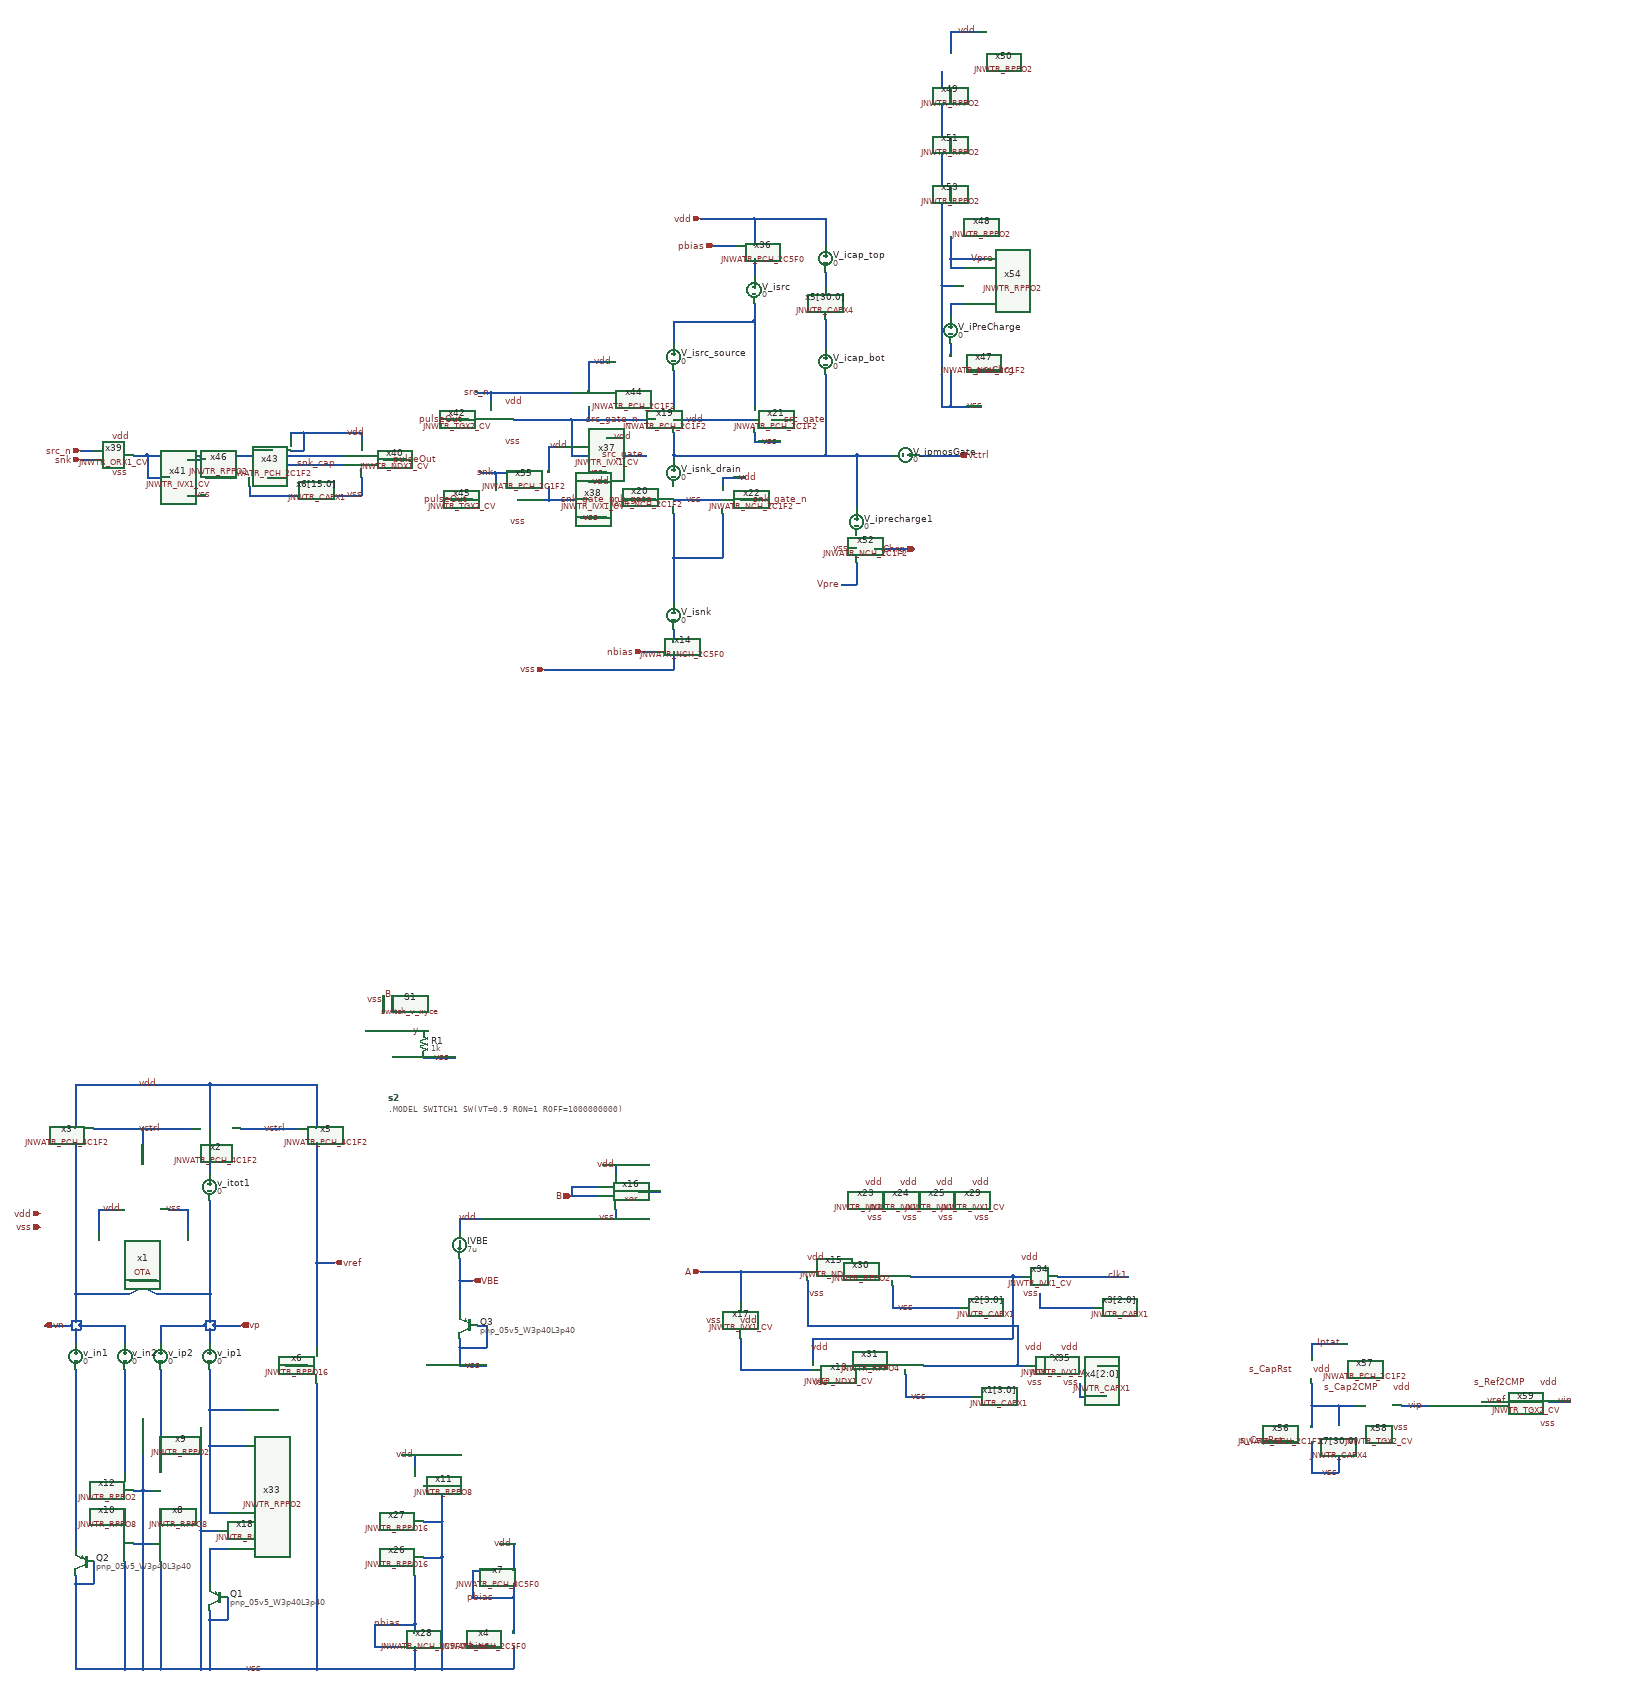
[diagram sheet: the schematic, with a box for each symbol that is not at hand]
v {xschem version=3.4.6 file_version=1.2}
G {}
K {}
V {}
S {}
E {}
N 870 -120 960 -120 {
lab=nbias}
N 960 -120 960 -100 {
lab=nbias}
N 1180 -210 1180 -180 {
lab=pbias}
N 1090 -180 1180 -180 {
lab=pbias}
N 1090 -240 1090 -180 {
lab=pbias}
N 1090 -240 1140 -240 {
lab=pbias}
N 1180 -300 1180 -240 {
lab=vdd}
N 960 -70 960 -20 {
lab=vss}
N 930 -500 960 -500 {
lab=vdd}
N 1020 -270 1020 -20 {
lab=vss}
N 980 -270 1020 -270 {
lab=vss}
N 1020 -350 1020 -270 {
lab=vss}
N 980 -350 1020 -350 {
lab=vss}
N 1020 -430 1020 -350 {
lab=vss}
N 980 -430 1020 -430 {
lab=vss}
N 960 -500 960 -470 {
lab=vdd}
N 1090 -70 1140 -70 {
lab=nbias}
N 1020 -20 1180 -20 {
lab=vss}
N 1150 -300 1180 -300 {
lab=vdd}
N 870 -120 870 -70 {
lab=nbias}
N 870 -70 920 -70 {
lab=nbias}
N 1180 -70 1180 -20 {
lab=vss}
N 1180 -180 1180 -100 {
lab=pbias}
N 960 -230 960 -120 {
lab=nbias}
N 490 -790 490 -780 {
lab=vp}
N 500 -800 510 -800 {
lab=vp}
N 210 -790 210 -780 {
lab=vn}
N 200 -800 210 -800 {
lab=vn}
N 510 -790 510 -780 {
lab=vp}
N 210 -800 210 -790 {
lab=vn}
N 490 -800 490 -790 {
lab=vp}
N 390 -790 490 -790 {
lab=vp}
N 200 -780 210 -780 {
lab=vn}
N 210 -790 310 -790 {
lab=vn}
N 190 -790 190 -780 {
lab=vn}
N 240 -260 240 -210 {
lab=vss}
N 200 -210 240 -210 {
lab=vss}
N 200 -230 200 -210 {
lab=vss}
N 540 -180 540 -130 {
lab=vss}
N 500 -130 540 -130 {
lab=vss}
N 500 -150 500 -130 {
lab=vss}
N 500 -780 510 -780 {
lab=vp}
N 380 -860 500 -860 {
lab=vp}
N 200 -860 200 -800 {
lab=vn}
N 190 -800 200 -800 {
lab=vn}
N 500 -860 500 -800 {
lab=vp}
N 490 -800 500 -800 {
lab=vp}
N 200 -1200 200 -860 {
lab=vn}
N 200 -860 320 -860 {
lab=vn}
N 350 -1230 350 -1150 {
lab=vctrl}
N 350 -1230 460 -1230 {
lab=vctrl}
N 240 -1230 350 -1230 {
lab=vctrl}
N 200 -1330 200 -1230 {
lab=vdd}
N 200 -1330 500 -1330 {
lab=vdd}
N 740 -1330 740 -1230 {
lab=vdd}
N 500 -1330 740 -1330 {
lab=vdd}
N 500 -1330 500 -1230 {
lab=vdd}
N 740 -930 740 -740 {
lab=vref}
N 510 -790 570 -790 {
lab=vp}
N 510 -800 510 -790 {
lab=vp}
N 130 -790 190 -790 {
lab=vn}
N 190 -800 190 -790 {
lab=vn}
N 740 -930 780 -930 {
lab=vref}
N 740 -1200 740 -930 {
lab=vref}
N 570 -1230 700 -1230 {
lab=vctrl}
N 500 -130 500 -20 {
lab=vss}
N 200 -210 200 -20 {
lab=vss}
N 500 -20 740 -20 {
lab=vss}
N 670 -700 720 -700 {
lab=vss}
N 740 -660 740 -20 {
lab=vss}
N 960 -20 1020 -20 {
lab=vss}
N 740 -20 960 -20 {
lab=vss}
N 480 -20 500 -20 {
lab=vss}
N 500 -1200 500 -1130 {
lab=#net1}
N 500 -780 500 -750 {
lab=vp}
N 490 -780 500 -780 {
lab=vp}
N 390 -790 390 -750 {
lab=vp}
N 200 -780 200 -750 {
lab=vn}
N 190 -780 200 -780 {
lab=vn}
N 200 -690 200 -290 {
lab=#net2}
N 310 -790 310 -750 {
lab=vn}
N 1060 -890 1060 -820 {
lab=VBE}
N 1060 -740 1060 -700 {
lab=vss}
N 1060 -700 1120 -700 {
lab=vss}
N 1060 -1030 1060 -1000 {
lab=vdd}
N 1060 -1030 1110 -1030 {
lab=vdd}
N 1060 -890 1090 -890 {
lab=VBE}
N 1060 -940 1060 -890 {
lab=VBE}
N 1100 -790 1120 -790 {
lab=vss}
N 1120 -790 1120 -740 {
lab=vss}
N 1060 -740 1120 -740 {
lab=vss}
N 1060 -760 1060 -740 {
lab=vss}
N 1310 -1100 1370 -1100 {
lab=B}
N 1310 -1080 1370 -1080 {
lab=B}
N 1410 -1150 1410 -1130 {
lab=vdd}
N 1380 -1150 1410 -1150 {
lab=vdd}
N 1410 -1050 1410 -1030 {
lab=vss}
N 1380 -1030 1410 -1030 {
lab=vss}
N 1460 -1090 1510 -1090 {
lab=#net3}
N 500 -520 500 -370 {
lab=#net4}
N 350 -300 370 -300 {
lab=vss}
N 330 -300 350 -300 {
lab=vss}
N 350 -420 370 -420 {
lab=vss}
N 330 -420 350 -420 {
lab=vss}
N 350 -420 350 -300 {
lab=vss}
N 350 -580 350 -420 {
lab=vss}
N 500 -520 580 -520 {
lab=#net4}
N 500 -600 580 -600 {
lab=#net4}
N 310 -690 310 -460 {
lab=#net5}
N 390 -690 390 -460 {
lab=#net6}
N 500 -690 500 -600 {
lab=#net4}
N 500 -290 500 -210 {
lab=#net7}
N 480 -330 480 -20 {
lab=vss}
N 390 -20 480 -20 {
lab=vss}
N 350 -300 350 -20 {
lab=vss}
N 310 -260 310 -20 {
lab=vss}
N 200 -20 310 -20 {
lab=vss}
N 390 -260 390 -20 {
lab=vss}
N 350 -20 390 -20 {
lab=vss}
N 310 -20 350 -20 {
lab=vss}
N 500 -1070 500 -860 {
lab=vp}
N 320 -860 380 -890 {
lab=vn}
N 320 -890 380 -860 {
lab=vp}
N 250 -1050 250 -1000 {
lab=vdd}
N 250 -1050 290 -1050 {
lab=vdd}
N 450 -1050 450 -1000 {
lab=vss}
N 410 -1050 450 -1050 {
lab=vss}
N 940 -1450 980 -1450 {
lab=y}
N 890 -1530 890 -1490 {
lab=vss}
N 910 -1530 910 -1490 {
lab=B}
N 850 -1450 880 -1450 {
lab=#net8}
N 980 -1390 1050 -1390 {
lab=vss}
N 1690 -760 1690 -690 {
lab=#net9}
N 1690 -690 1850 -690 {
lab=#net9}
N 1690 -910 1840 -910 {
lab=A}
N 1690 -910 1690 -840 {
lab=A}
N 1600 -910 1690 -910 {
lab=A}
N 1940 -700 2020 -700 {
lab=#net10}
N 2310 -790 2310 -700 {
lab=#net11}
N 1840 -790 2310 -790 {
lab=#net11}
N 1840 -890 1840 -790 {
lab=#net11}
N 1930 -900 1990 -900 {
lab=#net12}
N 2300 -900 2300 -760 {
lab=#net13}
N 1850 -760 2300 -760 {
lab=#net13}
N 1850 -760 1850 -710 {
lab=#net13}
N 1310 -1100 1310 -1080 {
lab=B}
N 2300 -900 2320 -900 {
lab=#net13}
N 2060 -680 2060 -630 {
lab=vss}
N 2100 -700 2310 -700 {
lab=#net11}
N 2060 -630 2210 -630 {
lab=vss}
N 2030 -880 2030 -830 {
lab=vss}
N 2070 -900 2300 -900 {
lab=#net13}
N 2030 -830 2180 -830 {
lab=vss}
N 2310 -700 2330 -700 {
lab=#net11}
N 2400 -900 2560 -900 {
lab=clk1}
N 2490 -700 2530 -700 {
lab=clk2}
N 2450 -660 2450 -630 {
lab=vss}
N 2450 -630 2510 -630 {
lab=vss}
N 2360 -860 2360 -830 {
lab=vss}
N 2360 -830 2480 -830 {
lab=vss}
N 480 -330 520 -330 {lab=vss}
N 480 -560 480 -330 {
lab=vss}
N 500 -370 540 -370 {lab=#net4}
N 500 -290 540 -290 {lab=#net7}
N 500 -600 500 -520 {lab=#net4}
N 390 -380 390 -340 {lab=#net14}
N 310 -380 310 -340 {lab=#net15}
N 1600 -3270 1720 -3270 {
lab=vdd}
N 1720 -3270 1720 -3210 {
lab=vdd}
N 1540 -2300 1540 -2260 {
lab=vss}
N 1630 -3210 1680 -3210 {
lab=pbias}
N 1470 -2300 1500 -2300 {
lab=nbias}
N 2160 -3180 2240 -3180 {
lab=Vpre}
N 1540 -2790 1540 -2740 {
lab=#net16}
N 1720 -2790 1720 -2770 {
lab=vss}
N 1720 -2770 1780 -2770 {
lab=vss}
N 1760 -2820 1785 -2820 {
lab=src_gate}
N 1650 -2690 1650 -2670 {
lab=vdd}
N 1650 -2690 1700 -2690 {
lab=vdd}
N 1690 -2640 1740 -2640 {
lab=snk_gate_n}
N 1540 -2350 1540 -2320 {
lab=#net17}
N 1720 -3180 1720 -3140 {
lab=#net18}
N 600 -2740 800 -2740 {
lab=#net19}
N 840 -2790 840 -2770 {
lab=vdd}
N 840 -2690 840 -2650 {
lab=vss}
N 360 -2740 360 -2690 {
lab=#net19}
N 650 -2720 650 -2690 {
lab=snk_cap}
N 650 -2720 800 -2720 {
lab=snk_cap}
N 590 -2670 590 -2650 {
lab=vss}
N 630 -2690 650 -2690 {
lab=snk_cap}
N 1350 -2820 1500 -2820 {
lab=src_gate_n}
N 1385 -2700 1390 -2700 {
lab=vss}
N 1390 -2780 1405 -2780 {
lab=vdd}
N 1310 -2820 1310 -2740 {
lab=src_gate_n}
N 1310 -2740 1350 -2740 {
lab=src_gate_n}
N 1430 -2740 1480 -2740 {
lab=src_gate}
N 1430 -2640 1500 -2640 {
lab=snk_gate}
N 1350 -2680 1390 -2680 {
lab=vdd}
N 490 -2690 550 -2690 {
lab=#net20}
N 360 -2690 410 -2690 {
lab=#net19}
N 450 -2650 490 -2650 {
lab=vss}
N 450 -2730 490 -2730 {
lab=vdd}
N 590 -2650 840 -2650 {
lab=vss}
N 1330 -2600 1390 -2600 {
lab=vss}
N 330 -2740 360 -2740 {
lab=#net19}
N 680 -2790 680 -2780 {
lab=vdd}
N 710 -2790 840 -2790 {
lab=vdd}
N 600 -2750 640 -2750 {
lab=#net19}
N 600 -2750 600 -2740 {
lab=#net19}
N 360 -2740 600 -2740 {
lab=#net19}
N 680 -2750 710 -2750 {
lab=vdd}
N 710 -2790 710 -2750 {
lab=vdd}
N 680 -2790 710 -2790 {
lab=vdd}
N 2160 -2930 2160 -2850 {
lab=vss}
N 2200 -2930 2270 -2930 {
lab=preChrg}
N 2160 -2990 2160 -2960 {
lab=#net21}
N 2160 -3080 2160 -3050 {
lab=#net22}
N 2160 -2850 2230 -2850 {
lab=vss}
N 2140 -2850 2160 -2850 {
lab=vss}
N 2160 -3560 2160 -3530 {
lab=#net23}
N 2160 -3690 2160 -3640 {
lab=vdd}
N 2160 -3690 2220 -3690 {
lab=vdd}
N 2160 -3450 2160 -3420 {
lab=#net24}
N 1540 -2740 1540 -2730 {
lab=#net16}
N 1540 -3040 1720 -3040 {
lab=#net25}
N 1720 -3080 1720 -3040 {
lab=#net25}
N 1720 -3270 1880 -3270 {
lab=vdd}
N 1540 -2820 1720 -2820 {
lab=vdd}
N 1540 -2640 1650 -2640 {
lab=vss}
N 1540 -2510 1540 -2410 {
lab=#net26}
N 1650 -2610 1650 -2510 {
lab=#net26}
N 1540 -2510 1650 -2510 {
lab=#net26}
N 1540 -2610 1540 -2510 {
lab=#net26}
N 1720 -3040 1720 -2850 {
lab=#net25}
N 1880 -3045 1880 -2980 {
lab=#net27}
N 1880 -2920 1880 -2740 {
lab=#net16}
N 1540 -2740 1880 -2740 {
lab=#net16}
N 1950 -2740 2030 -2740 {
lab=#net16}
N 2090 -2740 2180 -2740 {
lab=vctrl}
N 1880 -3150 1880 -3115 {
lab=#net28}
N 1880 -3270 1880 -3210 {
lab=vdd}
N 1540 -3040 1540 -2990 {
lab=#net25}
N 1540 -2930 1540 -2850 {
lab=#net29}
N 1990 -2530 2080 -2530 {
lab=preChrg}
N 1935 -2530 1950 -2530 {
lab=vss}
N 1950 -2500 1950 -2450 {
lab=Vpre}
N 1915 -2450 1950 -2450 {
lab=Vpre}
N 1950 -2740 1950 -2620 {
lab=#net16}
N 1880 -2740 1950 -2740 {
lab=#net16}
N 2160 -3180 2160 -3160 {lab=Vpre}
N 2140 -3120 2140 -2850 {
lab=vss}
N 2160 -3160 2190 -3160 {lab=Vpre}
N 2160 -3080 2190 -3080 {lab=#net22}
N 2140 -3120 2170 -3120 {lab=vss}
N 2160 -3230 2160 -3180 {lab=Vpre}
N 2160 -3340 2160 -3310 {lab=#net30}
N 2140 -3600 2140 -3120 {
lab=vss}
N 210 -2730 240 -2730 {lab=snk}
N 210 -2750 240 -2750 {lab=src_n}
N 890 -2730 940 -2730 {lab=pulseOut}
N 1130 -2880 1130 -2860 {lab=src_n}
N 1100 -2880 1130 -2880 {lab=src_n}
N 1180 -2820 1310 -2820 {lab=src_gate_n}
N 1030 -2820 1080 -2820 {lab=pulseOut}
N 1350 -2850 1350 -2820 {lab=src_gate_n}
N 1310 -2820 1350 -2820 {
lab=src_gate_n}
N 1350 -2950 1350 -2880 {lab=vdd}
N 1350 -2950 1390 -2950 {lab=vdd}
N 1130 -2880 1310 -2880 {lab=src_n}
N 1140 -2700 1140 -2680 {lab=snk}
N 1110 -2700 1140 -2700 {lab=snk}
N 1040 -2640 1090 -2640 {lab=pulseOut}
N 1260 -2640 1350 -2640 {lab=snk_gate_n}
N 1250 -2260 1540 -2260 {
lab=vss}
N 1140 -2700 1220 -2700 {lab=snk}
N 1260 -2760 1260 -2700 {lab=vdd}
N 1260 -2760 1280 -2760 {lab=vdd}
N 1260 -2670 1260 -2640 {lab=snk_gate_n}
N 1190 -2640 1260 -2640 {lab=snk_gate_n}
N 2970 -460 3030 -460 {lab=vss}
N 3030 -495 3030 -460 {lab=vss}
N 2970 -530 2970 -460 {lab=vss}
N 2870 -530 2930 -530 {lab=s_CapRst}
N 3030 -610 3030 -565 {lab=#net1}
N 3030 -610 3070 -610 {lab=#net1}
N 2970 -610 2970 -560 {lab=#net1}
N 2970 -610 3030 -610 {lab=#net1}
N 2970 -660 2970 -610 {lab=#net1}
N 2970 -750 2970 -720 {lab=Iptat}
N 2970 -750 3030 -750 {lab=Iptat}
N 3170 -610 3230 -610 {lab=vip}
N 3350 -620 3400 -620 {lab=vref}
N 3500 -620 3550 -620 {lab=vin}
C {devices/ipin.sym} 120 -1010 0 0 {name=p4 lab=vss}
C {devices/ipin.sym} 120 -1040 0 0 {name=p5 lab=vdd}
C {devices/lab_wire.sym} 1140 -180 0 0 {name=p32 sig_type=std_logic lab=pbias}
C {devices/lab_wire.sym} 960 -500 0 0 {name=p34 sig_type=std_logic lab=vdd}
C {JNW_ATR_SKY130A/JNWATR_PCH_8C5F0.sym} 1140 -240 0 0 {name=x7 }
C {JNW_ATR_SKY130A/JNWATR_NCH_2C5F0.sym} 920 -70 0 0 {name=x28 }
C {devices/lab_wire.sym} 930 -120 0 0 {name=p12 sig_type=std_logic lab=nbias}
C {devices/lab_wire.sym} 1180 -300 0 0 {name=p13 sig_type=std_logic lab=vdd}
C {JNW_ATR_SKY130A/JNWATR_NCH_2C5F0.sym} 1140 -70 0 0 {name=x4 }
C {devices/lab_wire.sym} 1130 -70 0 0 {name=p14 sig_type=std_logic lab=nbias}
C {JNW_TR_SKY130A/JNWTR_RPPO16.sym} 960 -230 3 0 {name=x26 }
C {JNW_TR_SKY130A/JNWTR_RPPO16.sym} 960 -310 3 0 {name=x27 }
C {JNW_TR_SKY130A/JNWTR_RPPO8.sym} 960 -390 3 0 {name=x11 }
C {sky130_fd_pr/pnp_05v5.sym} 520 -180 0 1 {name=Q1
model=pnp_05v5_W3p40L3p40
m=8
spiceprefix=X
}
C {sky130_fd_pr/pnp_05v5.sym} 220 -260 0 1 {name=Q2
model=pnp_05v5_W3p40L3p40
m=1
spiceprefix=X
}
C {devices/lab_wire.sym} 340 -1330 0 1 {name=p29 sig_type=std_logic lab=vdd

}
C {devices/opin.sym} 130 -790 2 0 {name=p44 lab=vn}
C {JNW_ATR_SKY130A/JNWATR_PCH_4C1F2.sym} 460 -1230 0 0 {name=x2 }
C {JNW_ATR_SKY130A/JNWATR_PCH_4C1F2.sym} 240 -1230 0 1 {name=x3 }
C {JNW_ATR_SKY130A/JNWATR_PCH_4C1F2.sym} 700 -1230 0 0 {name=x5 }
C {devices/lab_wire.sym} 340 -1230 0 1 {name=p8 sig_type=std_logic lab=vctrl

}
C {devices/lab_wire.sym} 620 -1230 0 1 {name=p9 sig_type=std_logic lab=vctrl

}
C {devices/lab_wire.sym} 620 -20 0 0 {name=p3 sig_type=std_logic lab=vss
}
C {devices/opin.sym} 570 -790 0 0 {name=p7 lab=vp}
C {devices/opin.sym} 780 -930 0 0 {name=p10 lab=vref}
C {devices/lab_wire.sym} 700 -700 0 0 {name=p11 sig_type=std_logic lab=vss
}
C {JNW_TR_SKY130A/JNWTR_RPPO16.sym} 740 -740 1 0 {name=x6 }
C {devices/vsource.sym} 500 -1100 0 0 {name=v_itot1 value=0 savecurrent=true}
C {devices/vsource.sym} 500 -720 0 0 {name=v_ip1 value=0 savecurrent=true}
C {devices/vsource.sym} 390 -720 0 0 {name=v_ip2 value=0 savecurrent=true}
C {devices/vsource.sym} 200 -720 0 0 {name=v_in1 value=0 savecurrent=true}
C {devices/vsource.sym} 310 -720 0 0 {name=v_in2 value=0 savecurrent=true}
C {devices/isource.sym} 1060 -970 0 0 {name=IVBE value=7u}
C {devices/lab_wire.sym} 1100 -1030 0 0 {name=p15 sig_type=std_logic lab=vdd}
C {devices/lab_wire.sym} 1110 -700 0 0 {name=p16 sig_type=std_logic lab=vss
}
C {devices/opin.sym} 1090 -890 0 0 {name=p17 lab=VBE}
C {sky130_fd_pr/pnp_05v5.sym} 1080 -790 0 1 {name=Q3
model=pnp_05v5_W3p40L3p40
m=1
spiceprefix=X
}
C {devices/ipin.sym} 1310 -1080 0 0 {name=p18 lab=B}
C {JNW_AVV_SKY130A/xor.sym} 1410 -1090 0 0 {name=x16}
C {devices/lab_wire.sym} 1410 -1150 0 0 {name=p20 sig_type=std_logic lab=vdd}
C {devices/lab_wire.sym} 1410 -1030 0 0 {name=p21 sig_type=std_logic lab=vss
}
C {JNW_TR_SKY130A/JNWTR_RPPO2.sym} 500 -370 1 0 {name=x18 }
C {JNW_AVV_SKY130A/OTA.sym} 350 -1000 3 0 {name=x1}
C {devices/lab_wire.sym} 260 -1050 0 1 {name=p1 sig_type=std_logic lab=vdd

}
C {devices/lab_wire.sym} 440 -1050 0 0 {name=p2 sig_type=std_logic lab=vss
}
C {devices/lab_wire.sym} 890 -1520 0 0 {name=p6 sig_type=std_logic lab=vss
}
C {devices/lab_wire.sym} 910 -1530 0 0 {name=p24 sig_type=std_logic lab=B
}
C {devices/lab_wire.sym} 970 -1450 0 0 {name=p25 sig_type=std_logic lab=y
}
C {devices/switch_v_xyce.sym} 910 -1450 1 0 {.MODEL SWITCH1 SW(VT=0.5 VH=0.01 RON=0.01 ROFF=10000000)

name=S1 model=SWITCH1 state=OFF

}
C {devices/netlist.sym} 900 -1300 0 0 {name=s2 value=".MODEL SWITCH1 SW(VT=0.9 RON=1 ROFF=1000000000)"
}
C {devices/res.sym} 980 -1420 0 0 {name=R1
value=1k
footprint=1206
device=resistor
m=1}
C {devices/lab_wire.sym} 1040 -1390 0 0 {name=p22 sig_type=std_logic lab=vss
}
C {JNW_TR_SKY130A/JNWTR_NDX1_CV.sym} 1850 -690 0 0 {name=x13 }
C {devices/lab_wire.sym} 1890 -740 0 0 {name=p26 sig_type=std_logic lab=vdd}
C {devices/lab_wire.sym} 1890 -660 0 0 {name=p27 sig_type=std_logic lab=vss
}
C {JNW_TR_SKY130A/JNWTR_NDX1_CV.sym} 1840 -890 0 0 {name=x15 }
C {devices/lab_wire.sym} 1880 -940 0 0 {name=p28 sig_type=std_logic lab=vdd}
C {devices/lab_wire.sym} 1880 -860 0 0 {name=p30 sig_type=std_logic lab=vss
}
C {JNW_TR_SKY130A/JNWTR_IVX1_CV.sym} 1690 -840 1 0 {name=x17 }
C {devices/lab_wire.sym} 1650 -800 0 0 {name=p31 sig_type=std_logic lab=vss
}
C {devices/lab_wire.sym} 1730 -800 0 0 {name=p33 sig_type=std_logic lab=vdd}
C {devices/ipin.sym} 1600 -910 0 0 {name=p35 lab=A}
C {JNW_TR_SKY130A/JNWTR_IVX1_CV.sym} 1970 -1070 0 0 {name=x23 }
C {devices/lab_wire.sym} 2010 -1030 3 0 {name=p36 sig_type=std_logic lab=vss
}
C {devices/lab_wire.sym} 2010 -1110 3 0 {name=p37 sig_type=std_logic lab=vdd}
C {JNW_TR_SKY130A/JNWTR_IVX1_CV.sym} 2050 -1070 0 0 {name=x24 }
C {devices/lab_wire.sym} 2090 -1030 3 0 {name=p38 sig_type=std_logic lab=vss
}
C {devices/lab_wire.sym} 2090 -1110 3 0 {name=p39 sig_type=std_logic lab=vdd}
C {JNW_TR_SKY130A/JNWTR_IVX1_CV.sym} 2130 -1070 0 0 {name=x25 }
C {devices/lab_wire.sym} 2170 -1030 3 0 {name=p40 sig_type=std_logic lab=vss
}
C {devices/lab_wire.sym} 2170 -1110 3 0 {name=p41 sig_type=std_logic lab=vdd}
C {JNW_TR_SKY130A/JNWTR_IVX1_CV.sym} 2210 -1070 0 0 {name=x29 }
C {devices/lab_wire.sym} 2250 -1030 3 0 {name=p42 sig_type=std_logic lab=vss
}
C {devices/lab_wire.sym} 2250 -1110 3 0 {name=p43 sig_type=std_logic lab=vdd}
C {devices/lab_wire.sym} 2560 -900 0 0 {name=p53 sig_type=std_logic lab=clk1}
C {devices/lab_wire.sym} 2530 -700 0 0 {name=p54 sig_type=std_logic lab=clk2}
C {JNW_TR_SKY130A/JNWTR_IVX1_CV.sym} 2320 -900 0 0 {name=x34 }
C {devices/lab_wire.sym} 2360 -860 3 0 {name=p19 sig_type=std_logic lab=vss
}
C {devices/lab_wire.sym} 2360 -940 3 0 {name=p23 sig_type=std_logic lab=vdd}
C {JNW_TR_SKY130A/JNWTR_CAPX1.sym} 2210 -640 0 0 {name=x1[3:0]}
C {devices/lab_wire.sym} 2110 -630 3 0 {name=p45 sig_type=std_logic lab=vss
}
C {JNW_TR_SKY130A/JNWTR_CAPX1.sym} 2180 -840 0 0 {name=x2[3:0]}
C {devices/lab_wire.sym} 2080 -830 3 0 {name=p46 sig_type=std_logic lab=vss
}
C {JNW_TR_SKY130A/JNWTR_IVX1_CV.sym} 2330 -700 0 0 {name=x32 }
C {devices/lab_wire.sym} 2370 -660 3 0 {name=p47 sig_type=std_logic lab=vss
}
C {devices/lab_wire.sym} 2370 -740 3 0 {name=p48 sig_type=std_logic lab=vdd}
C {JNW_TR_SKY130A/JNWTR_IVX1_CV.sym} 2410 -700 0 0 {name=x35 }
C {devices/lab_wire.sym} 2450 -660 3 0 {name=p51 sig_type=std_logic lab=vss
}
C {devices/lab_wire.sym} 2450 -740 3 0 {name=p52 sig_type=std_logic lab=vdd}
C {JNW_TR_SKY130A/JNWTR_CAPX1.sym} 2480 -840 0 0 {name=x3[2:0]}
C {JNW_TR_SKY130A/JNWTR_CAPX1.sym} 2510 -640 0 0 {name=x4[2:0]}
C {JNW_TR_SKY130A/JNWTR_RPPO4.sym} 2020 -700 0 0 {name=x31 }
C {JNW_TR_SKY130A/JNWTR_RPPO2.sym} 1990 -900 0 0 {name=x30 }
C {JNW_TR_SKY130A/JNWTR_RPPO2.sym} 540 -370 1 0 {name=x33 }
C {JNW_TR_SKY130A/JNWTR_RPPO8.sym} 390 -340 1 0 {name=x8 }
C {JNW_TR_SKY130A/JNWTR_RPPO2.sym} 390 -460 1 0 {name=x9 }
C {JNW_TR_SKY130A/JNWTR_RPPO8.sym} 310 -340 3 1 {name=x10 }
C {JNW_TR_SKY130A/JNWTR_RPPO2.sym} 310 -460 3 1 {name=x12 }
C {devices/ipin.sym} 1600 -3270 0 0 {name=p49 lab=vdd}
C {devices/opin.sym} 2180 -2740 0 0 {name=p50 lab=vctrl}
C {devices/ipin.sym} 1250 -2260 0 0 {name=p55 lab=vss
}
C {devices/ipin.sym} 1470 -2300 0 0 {name=p56 lab=nbias
}
C {devices/ipin.sym} 1630 -3210 0 0 {name=p57 lab=pbias
}
C {JNW_TR_SKY130A/JNWTR_CAPX4.sym} 1880 -3055 0 0 {name=x5[30:0]}
C {devices/ipin.sym} 2080 -2530 2 0 {name=p58 lab=preChrg
}
C {devices/lab_wire.sym} 2175 -3690 0 1 {name=p59 sig_type=std_logic lab=vdd}
C {JNW_ATR_SKY130A/JNWATR_NCH_2C5F0.sym} 1500 -2300 0 0 {name=x14 }
C {devices/lab_wire.sym} 1565 -2820 0 1 {name=p60 sig_type=std_logic lab=vdd}
C {devices/lab_wire.sym} 2195 -2850 0 1 {name=p61 sig_type=std_logic lab=vss}
C {devices/lab_wire.sym} 2205 -3180 0 1 {name=p62 sig_type=std_logic lab=Vpre}
C {devices/lab_wire.sym} 1915 -2450 0 0 {name=p63 sig_type=std_logic lab=Vpre}
C {JNW_ATR_SKY130A/JNWATR_PCH_2C1F2.sym} 1500 -2820 0 0 {name=x19 }
C {JNW_ATR_SKY130A/JNWATR_NCH_2C1F2.sym} 1500 -2640 0 0 {name=x20 }
C {JNW_ATR_SKY130A/JNWATR_PCH_2C1F2.sym} 1760 -2820 0 1 {name=x21 }
C {devices/lab_wire.sym} 1775 -2770 0 0 {name=p64 sig_type=std_logic lab=vss}
C {devices/lab_wire.sym} 1785 -2820 0 1 {name=p65 sig_type=std_logic lab=src_gate}
C {JNW_ATR_SKY130A/JNWATR_NCH_2C1F2.sym} 1690 -2640 0 1 {name=x22 }
C {devices/lab_wire.sym} 1605 -2640 0 0 {name=p66 sig_type=std_logic lab=vss}
C {devices/lab_wire.sym} 1715 -2640 0 1 {name=p67 sig_type=std_logic lab=snk_gate_n}
C {devices/vsource.sym} 1720 -3110 0 0 {name=V_isrc value=0 savecurrent=true}
C {devices/vsource.sym} 1540 -2380 0 0 {name=V_isnk value=0 savecurrent=true}
C {JNW_ATR_SKY130A/JNWATR_PCH_2C5F0.sym} 1680 -3210 0 0 {name=x36 }
C {devices/ipin.sym} 210 -2730 0 0 {name=p68 lab=snk
}
C {devices/ipin.sym} 210 -2750 0 0 {name=p69 lab=src_n}
C {devices/lab_wire.sym} 805 -2790 0 1 {name=p70 sig_type=std_logic lab=vdd}
C {devices/lab_wire.sym} 805 -2650 0 1 {name=p71 sig_type=std_logic lab=vss}
C {devices/lab_wire.sym} 1465 -2820 0 0 {name=p72 sig_type=std_logic lab=src_gate_n}
C {devices/lab_wire.sym} 1495 -2640 0 0 {name=p73 sig_type=std_logic lab=snk_gate}
C {JNW_TR_SKY130A/JNWTR_CAPX1.sym} 740 -2660 0 0 {name=x6[15:0]}
C {devices/lab_wire.sym} 785 -2720 0 0 {name=p77 sig_type=std_logic lab=snk_cap}
C {JNW_TR_SKY130A/JNWTR_IVX1_CV.sym} 1350 -2740 0 0 {name=x37 }
C {devices/lab_wire.sym} 1405 -2780 0 1 {name=p78 sig_type=std_logic lab=vdd}
C {devices/lab_wire.sym} 1385 -2700 0 0 {name=p79 sig_type=std_logic lab=vss}
C {devices/lab_wire.sym} 1475 -2740 0 0 {name=p80 sig_type=std_logic lab=src_gate}
C {JNW_TR_SKY130A/JNWTR_IVX1_CV.sym} 1350 -2640 0 0 {name=x38 }
C {devices/lab_wire.sym} 1285 -2640 0 1 {name=p81 sig_type=std_logic lab=snk_gate_n}
C {JNW_TR_SKY130A/JNWTR_NDX1_CV.sym} 800 -2720 0 0 {name=x40 }
C {devices/lab_wire.sym} 1375 -2600 0 0 {name=p82 sig_type=std_logic lab=vss}
C {devices/lab_wire.sym} 1355 -2680 0 1 {name=p83 sig_type=std_logic lab=vdd}
C {JNW_TR_SKY130A/JNWTR_IVX1_CV.sym} 410 -2690 0 0 {name=x41 }
C {devices/lab_wire.sym} 465 -2650 0 1 {name=p84 sig_type=std_logic lab=vss}
C {devices/lab_wire.sym} 475 -2730 0 1 {name=p86 sig_type=std_logic lab=vdd}
C {JNW_ATR_SKY130A/JNWATR_PCH_2C1F2.sym} 640 -2750 0 0 {name=x43 }
C {JNW_TR_SKY130A/JNWTR_RPPO2.sym} 550 -2690 0 0 {name=x46 }
C {devices/vsource.sym} 2160 -3020 0 0 {name=V_iPreCharge value=0 savecurrent=true}
C {JNW_ATR_SKY130A/JNWATR_NCH_2C1F2.sym} 2200 -2930 0 1 {name=x47 }
C {devices/lab_wire.sym} 2215 -2930 0 1 {name=p88 sig_type=std_logic lab=preChrg}
C {JNW_TR_SKY130A/JNWTR_RPPO2.sym} 2160 -3160 1 0 {name=x48 }
C {JNW_TR_SKY130A/JNWTR_RPPO2.sym} 2160 -3530 1 0 {name=x49 }
C {JNW_TR_SKY130A/JNWTR_RPPO2.sym} 2160 -3640 1 0 {name=x50 }
C {JNW_TR_SKY130A/JNWTR_RPPO2.sym} 2160 -3420 1 0 {name=x51 }
C {devices/vsource.sym} 1540 -2700 0 0 {name=V_isnk_drain value=0 savecurrent=true}
C {devices/vsource.sym} 1540 -2960 0 0 {name=V_isrc_source value=0 savecurrent=true}
C {devices/lab_wire.sym} 1685 -2690 0 1 {name=p89 sig_type=std_logic lab=vdd}
C {devices/vsource.sym} 1880 -2950 0 0 {name=V_icap_bot value=0 savecurrent=true}
C {devices/vsource.sym} 1950 -2590 0 0 {name=V_iprecharge1 value=0 savecurrent=true}
C {devices/vsource.sym} 2060 -2740 1 0 {name=V_ipmosGate value=0 savecurrent=true}
C {devices/vsource.sym} 1880 -3180 0 0 {name=V_icap_top value=0 savecurrent=true}
C {JNW_ATR_SKY130A/JNWATR_NCH_2C1F2.sym} 1990 -2530 0 1 {name=x52 }
C {devices/lab_wire.sym} 1935 -2530 0 0 {name=p90 sig_type=std_logic lab=vss}
C {JNW_TR_SKY130A/JNWTR_RPPO2.sym} 2160 -3310 1 0 {name=x53 }
C {JNW_TR_SKY130A/JNWTR_RPPO2.sym} 2190 -3160 1 0 {name=x54 }
C {JNW_TR_SKY130A/JNWTR_ORX1_CV.sym} 240 -2730 0 0 {name=x39 }
C {devices/lab_wire.sym} 280 -2780 0 1 {name=p74 sig_type=std_logic lab=vdd

}
C {devices/lab_wire.sym} 280 -2700 0 1 {name=p75 sig_type=std_logic lab=vss

}
C {devices/lab_wire.sym} 910 -2730 0 1 {name=p76 sig_type=std_logic lab=pulseOut

}
C {JNW_TR_SKY130A/JNWTR_TGX2_CV.sym} 1070 -2820 0 0 {name=x42 }
C {devices/lab_wire.sym} 1160 -2860 0 1 {name=p85 sig_type=std_logic lab=vdd

}
C {devices/lab_wire.sym} 1160 -2770 0 1 {name=p87 sig_type=std_logic lab=vss

}
C {devices/lab_wire.sym} 1130 -2880 0 0 {name=p91 sig_type=std_logic lab=src_n

}
C {devices/lab_wire.sym} 1070 -2820 0 0 {name=p92 sig_type=std_logic lab=pulseOut

}
C {devices/lab_wire.sym} 1360 -2950 0 1 {name=p93 sig_type=std_logic lab=vdd

}
C {JNW_TR_SKY130A/JNWTR_TGX2_CV.sym} 1080 -2640 0 0 {name=x45 }
C {devices/lab_wire.sym} 1170 -2680 0 1 {name=p94 sig_type=std_logic lab=vdd

}
C {devices/lab_wire.sym} 1170 -2590 0 1 {name=p95 sig_type=std_logic lab=vss

}
C {devices/lab_wire.sym} 1140 -2700 0 0 {name=p96 sig_type=std_logic lab=snk

}
C {devices/lab_wire.sym} 1080 -2640 0 0 {name=p97 sig_type=std_logic lab=pulseOut

}
C {JNW_ATR_SKY130A/JNWATR_PCH_2C1F2.sym} 1310 -2880 0 0 {name=x44 }
C {JNW_ATR_SKY130A/JNWATR_PCH_2C1F2.sym} 1220 -2700 0 0 {name=x55 }
C {devices/lab_wire.sym} 1260 -2760 0 1 {name=p98 sig_type=std_logic lab=vdd

}
C {JNW_TR_SKY130A/JNWTR_CAPX4.sym} 3030 -505 0 0 {name=x7[30:0]}
C {JNW_ATR_SKY130A/JNWATR_NCH_2C1F2.sym} 2930 -530 0 0 {name=x56 }
C {devices/lab_wire.sym} 2910 -530 0 0 {name=p99 sig_type=std_logic lab=s_CapRst}
C {JNW_ATR_SKY130A/JNWATR_PCH_2C1F2.sym} 2930 -690 0 0 {name=x57 }
C {devices/lab_wire.sym} 2930 -690 0 0 {name=p100 sig_type=std_logic lab=s_CapRst}
C {devices/lab_wire.sym} 2970 -690 0 1 {name=p101 sig_type=std_logic lab=vdd}
C {devices/lab_wire.sym} 2980 -750 0 1 {name=p102 sig_type=std_logic lab=Iptat}
C {JNW_TR_SKY130A/JNWTR_TGX2_CV.sym} 3060 -610 0 0 {name=x58 }
C {devices/lab_wire.sym} 3150 -560 0 1 {name=p103 sig_type=std_logic lab=vss}
C {devices/lab_wire.sym} 3150 -650 0 1 {name=p104 sig_type=std_logic lab=vdd}
C {devices/lab_wire.sym} 3220 -610 0 0 {name=p105 sig_type=std_logic lab=vip}
C {JNW_TR_SKY130A/JNWTR_TGX2_CV.sym} 3390 -620 0 0 {name=x59 }
C {devices/lab_wire.sym} 3480 -570 0 1 {name=p106 sig_type=std_logic lab=vss}
C {devices/lab_wire.sym} 3480 -660 0 1 {name=p107 sig_type=std_logic lab=vdd}
C {devices/lab_wire.sym} 3360 -620 0 1 {name=p108 sig_type=std_logic lab=vref}
C {devices/lab_wire.sym} 3520 -620 0 1 {name=p109 sig_type=std_logic lab=vin}
C {devices/lab_wire.sym} 3450 -660 0 0 {name=p110 sig_type=std_logic lab=s_Ref2CMP}
C {devices/lab_wire.sym} 3120 -650 0 0 {name=p111 sig_type=std_logic lab=s_Cap2CMP}
C {devices/lab_wire.sym} 2990 -460 0 1 {name=p112 sig_type=std_logic lab=vss}
